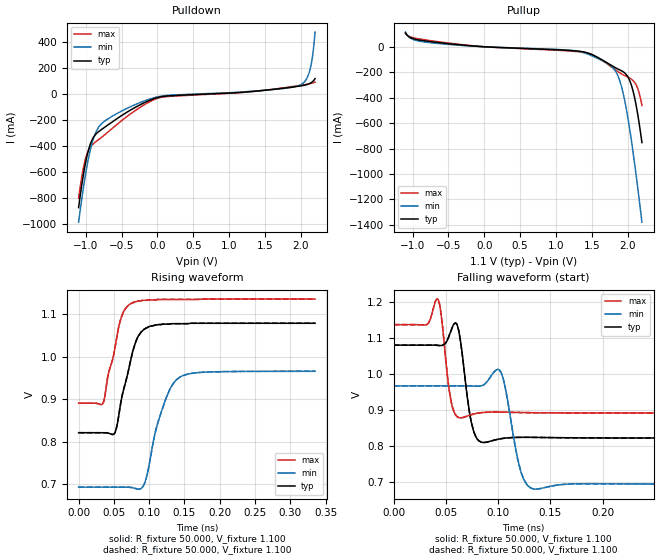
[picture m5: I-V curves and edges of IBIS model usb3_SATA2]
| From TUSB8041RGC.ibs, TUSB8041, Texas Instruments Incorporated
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|   USB 3.0 SATA2 mode, for SSTXP/N pin 1.5GHz
[Model]   usb3_SATA2
Model_type   Output
Polarity   Non-Inverting
Vmeas = 0.96V
Vref = 1.1
Rref = 50
|   typ   min   max
|   (nom PVT)   (Fast PVT)   (slow PVT)
C_comp   0.5279pF   0.5159pF   0.5468pF
[Voltage Range]   1.1   0.99   1.155
[Temperature Range]   27   105   -40
[Pullup Reference]   1.1   0.99   1.155
[Pulldown Reference]   -0   -0   -0
[Power Clamp Reference]   1.1   0.99   1.155
[GND Clamp Reference]   -0   -0   -0
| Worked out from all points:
|   slope of the pulldown table from 0 to 0.165 V, typ, clamps not added: 12 ohm
|   slope of the pullup table from 0 to 0.165 V, typ, clamps not added: 36.3 ohm
|   falling waveform, R_fixture 50.000, V_fixture 1.100: 20-80 % time 7.05ps typ, 10.1ps min, 5.71ps max; typ from 1.08 V to 0.821 V
|   rising waveform, R_fixture 50.000, V_fixture 1.100: 20-80 % time 21.5ps typ, 25.9ps min, 19.4ps max; typ from 0.821 V to 1.08 V
|   rising waveform, R_fixture 50.000, V_fixture 1.100: 20-80 % time 21.5ps typ, 25.9ps min, 19.4ps max; typ from 0.821 V to 1.08 V
|   falling waveform, R_fixture 50.000, V_fixture 1.100: 20-80 % time 7.05ps typ, 10.1ps min, 5.71ps max; typ from 1.08 V to 0.821 V
[Pulldown]
|   Voltage   I(typ)   I(min)   I(max)
-1.1V     -871mA     -982.9mA   -799.2mA
-1.026V   -593.6mA   -691.8mA   -545.9mA
-951.1mV  -407.6mA   -463mA     -418.8mA
-860.2mV  -306.9mA   -292.7mA   -364.5mA
-752.6mV  -259.4mA   -212.3mA   -318.6mA
-297.7mV  -96.41mA   -75.84mA   -120.1mA
33.08mV   -20.42mA   -15.62mA   -25.4mA
1.977V    63.15mA    68.04mA    67.72mA
2.059V    71.46mA    101.2mA    74.73mA
2.117V    81.47mA    166.2mA    80.6mA
2.167V    98.58mA    300.4mA    87.59mA
2.2V      121.3mA    478.8mA    94.41mA
[Pullup]
|   Voltage   I(typ)   I(min)   I(max)
-1.1V     109.5mA    116.7mA    106.1mA
-1.001V   66.16mA    60.09mA    73.56mA
-769.2mV  43.03mA    34.07mA    50.99mA
0V        1.097mA    1.053mA    1.136mA
1.414V    -42.99mA   -49.98mA   -44.91mA
1.77V     -144mA     -150.4mA   -155.7mA
1.869V    -175.2mA   -233.6mA   -196mA
1.96V     -205.2mA   -423.5mA   -225.7mA
2.026V    -260.9mA   -636.3mA   -244.6mA
2.084V    -365.6mA   -861.5mA   -270mA
2.142V    -533.2mA   -1.112A    -329.2mA
2.2V      -752.5mA   -1.379A    -460.8mA
[Ramp]
R_load = 50.00Ohm
|   typ   min   max
dV/dt_r   154.647mV/21.439ps  160.448mV/25.926ps  146.782mV/19.309ps
dV/dt_f   154.647mV/7.097ps   160.450mV/10.104ps  146.781mV/5.709ps
[Falling Waveform]
R_fixture = 50.000
V_fixture = 1.100
V_fixture_min = 0.990
V_fixture_max = 1.155
|  time   V(typ)   V(min)   V(max)
0s        1.079V     966mV      1.136V
42.58ps   1.078V     966mV      1.206V
54.88ps   1.119V     966mV      924.1mV
62.38ps   1.118V     966mV      877.8mV
73.88ps   870.6mV    965.6mV    885.5mV
83.7ps    809.8mV    965.9mV    891.4mV
102.7ps   819.2mV    1.004V     893mV
121.5ps   823mV      729.6mV    891.9mV
131.6ps   823mV      681.5mV    891.5mV
335.1ps   821.3mV    693.1mV    890.9mV
[Rising Waveform]
R_fixture = 50.000
V_fixture = 1.100
V_fixture_min = 0.990
V_fixture_max = 1.155
|  time   V(typ)   V(min)   V(max)
0s        821.3mV    693.1mV    890.9mV
33.47ps   821.2mV    693.1mV    888mV
51.11ps   820.2mV    693mV      1.017V
60.71ps   900.4mV    693mV      1.094V
75.76ps   1.006V     692mV      1.127V
92.73ps   1.065V     699.3mV    1.133V
117.5ps   1.076V     871.5mV    1.135V
131.6ps   1.078V     930.4mV    1.135V
142.3ps   1.078V     950.8mV    1.135V
335.1ps   1.079V     966mV      1.136V
[Rising Waveform]
R_fixture = 50.000
V_fixture = 1.100
V_fixture_min = 0.990
V_fixture_max = 1.155
|  time   V(typ)   V(min)   V(max)
0s        821.3mV    693.1mV    890.9mV
33.47ps   821.2mV    693.1mV    888mV
51.11ps   820.2mV    693mV      1.017V
60.71ps   900.4mV    693mV      1.094V
75.76ps   1.006V     692mV      1.127V
92.73ps   1.065V     699.3mV    1.133V
117.5ps   1.076V     871.5mV    1.135V
131.6ps   1.078V     930.4mV    1.135V
142.3ps   1.078V     950.8mV    1.135V
335.1ps   1.079V     966mV      1.136V
[Falling Waveform]
R_fixture = 50.000
V_fixture = 1.100
V_fixture_min = 0.990
V_fixture_max = 1.155
|  time   V(typ)   V(min)   V(max)
0s        1.079V     966mV      1.136V
42.58ps   1.078V     966mV      1.206V
54.88ps   1.119V     966mV      924.1mV
62.38ps   1.118V     966mV      877.8mV
73.88ps   870.6mV    965.6mV    885.5mV
83.7ps    809.8mV    965.9mV    891.4mV
102.7ps   819.2mV    1.004V     893mV
121.5ps   823mV      729.6mV    891.9mV
131.6ps   823mV      681.5mV    891.5mV
335.1ps   821.3mV    693.1mV    890.9mV
